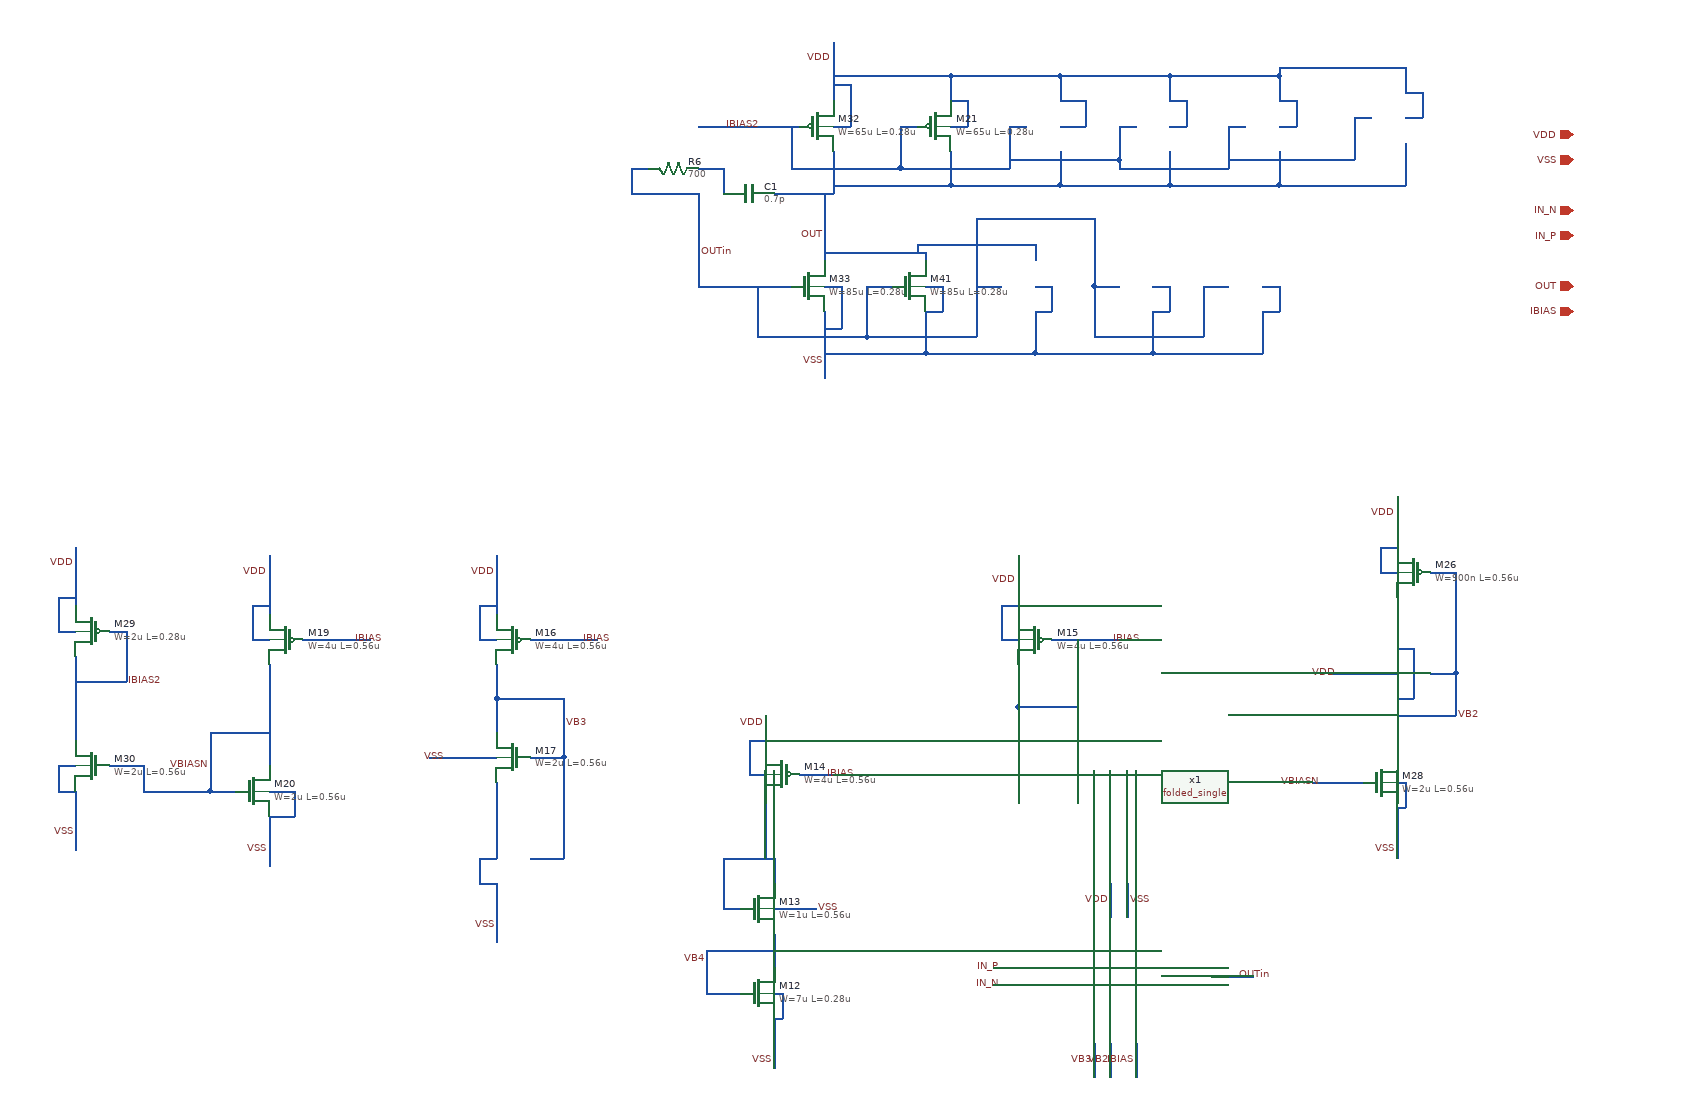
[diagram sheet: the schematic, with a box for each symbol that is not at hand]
v {xschem version=3.1.0 file_version=1.2
}
G {}
K {}
V {}
S {}
E {}
N 120 -50 120 20 {
lab=VDD}
N 100 50 120 50 {
lab=VDD}
N 100 10 100 50 {
lab=VDD}
N 100 10 120 10 {
lab=VDD}
N 160 50 240 50 {
lab=IBIAS}
N 120 80 120 130 {
lab=IBIAS}
N 120 130 190 130 {
lab=IBIAS}
N 190 50 190 130 {
lab=IBIAS}
N 120 130 120 180 {
lab=IBIAS}
N -500 -50 -500 20 {
lab=VDD}
N -520 50 -500 50 {
lab=VDD}
N -520 10 -520 50 {
lab=VDD}
N -520 10 -500 10 {
lab=VDD}
N -460 50 -380 50 {
lab=IBIAS}
N -500 340 -500 410 {
lab=VSS}
N -460 310 -420 310 {
lab=VB3}
N -420 260 -420 310 {
lab=VB3}
N -500 260 -500 280 {
lab=VSS}
N -500 220 -500 260 {
lab=VSS}
N -460 190 -420 190 {
lab=VB3}
N -420 190 -420 260 {
lab=VB3}
N -420 120 -420 190 {
lab=VB3}
N -500 120 -420 120 {
lab=VB3}
N -500 80 -500 120 {
lab=VB3}
N -500 120 -500 160 {
lab=VB3}
N -580 190 -500 190 {
lab=VSS}
N -520 310 -520 340 {
lab=VSS}
N -520 340 -500 340 {
lab=VSS}
N -770 -50 -770 20 {
lab=VDD}
N -790 50 -770 50 {
lab=VDD}
N -790 10 -790 50 {
lab=VDD}
N -790 10 -770 10 {
lab=VDD}
N -730 50 -650 50 {
lab=IBIAS}
N -770 80 -770 200 {
lab=VBIASN}
N -770 260 -770 320 {
lab=VSS}
N -770 230 -740 230 {
lab=VSS}
N -740 230 -740 260 {
lab=VSS}
N -770 260 -740 260 {
lab=VSS}
N -840 230 -810 230 {
lab=VBIASN}
N -840 160 -840 230 {
lab=VBIASN}
N -840 160 -770 160 {
lab=VBIASN}
N 570 120 570 190 {
lab=VB2}
N 570 220 580 220 {
lab=VSS}
N 580 220 580 250 {
lab=VSS}
N 570 250 580 250 {
lab=VSS}
N 570 250 570 310 {
lab=VSS}
N 470 220 530 220 {
lab=VBIASN}
N 550 90 570 90 {
lab=VDD}
N 570 0 570 60 {
lab=VB2}
N 490 90 550 90 {
lab=VDD}
N 570 -120 570 -60 {
lab=VDD}
N 610 -30 640 -30 {
lab=VB2}
N 570 140 640 140 {
lab=VB2}
N 610 90 640 90 {
lab=VB2}
N 550 -30 570 -30 {
lab=VDD}
N 550 -60 550 -30 {
lab=VDD}
N 550 -60 570 -60 {
lab=VDD}
N -1000 -60 -1000 10 {
lab=VDD}
N -1020 40 -1000 40 {
lab=VDD}
N -1020 0 -1020 40 {
lab=VDD}
N -1020 0 -1000 0 {
lab=VDD}
N -1000 230 -1000 300 {
lab=VSS}
N -1020 200 -1000 200 {
lab=VSS}
N -1020 200 -1020 230 {
lab=VSS}
N -1020 230 -1000 230 {
lab=VSS}
N -960 200 -920 200 {
lab=VBIASN}
N -920 200 -920 230 {
lab=VBIASN}
N -920 230 -840 230 {
lab=VBIASN}
N -1000 70 -1000 170 {
lab=IBIAS2}
N -960 40 -940 40 {
lab=IBIAS2}
N -940 40 -940 100 {
lab=IBIAS2}
N -1000 100 -940 100 {
lab=IBIAS2}
N -100 -660 -100 -590 {
lab=VDD}
N -100 -560 -80 -560 {
lab=VDD}
N -80 -610 -80 -560 {
lab=VDD}
N -100 -610 -80 -610 {
lab=VDD}
N -260 -560 -140 -560 {
lab=IBIAS2}
N -170 -480 -100 -480 {
lab=OUT}
N -100 -530 -100 -480 {
lab=OUT}
N -110 -480 -110 -400 {
lab=OUT}
N -110 -340 -110 -260 {
lab=VSS}
N -110 -370 -90 -370 {
lab=VSS}
N -90 -370 -90 -320 {
lab=VSS}
N -110 -320 -90 -320 {
lab=VSS}
N -260 -480 -260 -370 {
lab=OUTin}
N -260 -370 -150 -370 {
lab=OUTin}
N -20 -560 0 -560 {
lab=IBIAS2}
N -20 -560 -20 -510 {
lab=IBIAS2}
N -130 -510 -20 -510 {
lab=IBIAS2}
N -150 -510 -130 -510 {
lab=IBIAS2}
N -150 -560 -150 -510 {
lab=IBIAS2}
N 40 -620 40 -590 {
lab=VDD}
N -100 -620 40 -620 {
lab=VDD}
N 40 -560 60 -560 {
lab=VDD}
N 60 -590 60 -560 {
lab=VDD}
N 40 -590 60 -590 {
lab=VDD}
N 40 -530 40 -490 {
lab=OUT}
N -100 -490 40 -490 {
lab=OUT}
N -340 -510 -320 -510 {
lab=OUTin}
N -340 -510 -340 -480 {
lab=OUTin}
N -340 -480 -260 -480 {
lab=OUTin}
N -230 -510 -230 -480 {
lab=#net1}
N -260 -510 -230 -510 {
lab=#net1}
N 170 -620 170 -590 {
lab=VDD}
N 40 -620 170 -620 {
lab=VDD}
N 170 -530 170 -490 {
lab=OUT}
N 40 -490 170 -490 {
lab=OUT}
N 110 -560 130 -560 {
lab=IBIAS2}
N 110 -560 110 -510 {
lab=IBIAS2}
N -20 -510 110 -510 {
lab=IBIAS2}
N 170 -560 200 -560 {
lab=VDD}
N 200 -590 200 -560 {
lab=VDD}
N 170 -590 200 -590 {
lab=VDD}
N -60 -370 -30 -370 {
lab=OUTin}
N -60 -370 -60 -310 {
lab=OUTin}
N -190 -310 -60 -310 {
lab=OUTin}
N -190 -370 -190 -310 {
lab=OUTin}
N 10 -410 10 -400 {
lab=OUT}
N -110 -410 10 -410 {
lab=OUT}
N 10 -340 10 -290 {
lab=VSS}
N -110 -290 10 -290 {
lab=VSS}
N 10 -370 30 -370 {
lab=VSS}
N 30 -370 30 -340 {
lab=VSS}
N 10 -340 30 -340 {
lab=VSS}
N 300 -620 300 -590 {
lab=VDD}
N 170 -620 300 -620 {
lab=VDD}
N 300 -560 320 -560 {
lab=VDD}
N 320 -590 320 -560 {
lab=VDD}
N 300 -590 320 -590 {
lab=VDD}
N 240 -560 260 -560 {
lab=IBIAS2}
N 240 -560 240 -520 {
lab=IBIAS2}
N 110 -520 240 -520 {
lab=IBIAS2}
N 300 -530 300 -490 {
lab=OUT}
N 170 -490 300 -490 {
lab=OUT}
N 140 -420 140 -400 {
lab=OUT}
N 0 -420 140 -420 {
lab=OUT}
N 0 -420 0 -410 {
lab=OUT}
N 70 -370 100 -370 {
lab=OUTin}
N 70 -370 70 -310 {
lab=OUTin}
N -60 -310 70 -310 {
lab=OUTin}
N 10 -290 140 -290 {
lab=VSS}
N 140 -340 140 -290 {
lab=VSS}
N 140 -370 160 -370 {
lab=VSS}
N 160 -370 160 -340 {
lab=VSS}
N 140 -340 160 -340 {
lab=VSS}
N 430 -620 430 -590 {
lab=VDD}
N 300 -620 430 -620 {
lab=VDD}
N 300 -490 430 -490 {
lab=OUT}
N 430 -530 430 -490 {
lab=OUT}
N 430 -560 450 -560 {
lab=VDD}
N 450 -590 450 -560 {
lab=VDD}
N 430 -590 450 -590 {
lab=VDD}
N 370 -560 390 -560 {
lab=IBIAS2}
N 370 -560 370 -510 {
lab=IBIAS2}
N 240 -510 370 -510 {
lab=IBIAS2}
N 240 -520 240 -510 {
lab=IBIAS2}
N 210 -370 240 -370 {
lab=OUTin}
N 210 -370 210 -310 {
lab=OUTin}
N 280 -340 280 -290 {
lab=VSS}
N 280 -370 300 -370 {
lab=VSS}
N 300 -370 300 -340 {
lab=VSS}
N 280 -340 300 -340 {
lab=VSS}
N 340 -370 370 -370 {
lab=OUTin}
N 340 -370 340 -310 {
lab=OUTin}
N 210 -310 340 -310 {
lab=OUTin}
N 280 -290 410 -290 {
lab=VSS}
N 410 -340 410 -290 {
lab=VSS}
N 410 -370 430 -370 {
lab=VSS}
N 430 -370 430 -340 {
lab=VSS}
N 410 -340 430 -340 {
lab=VSS}
N 140 -290 280 -290 {
lab=VSS}
N 210 -450 210 -370 {
lab=OUTin}
N 70 -450 210 -450 {
lab=OUTin}
N 70 -450 70 -360 {
lab=OUTin}
N 580 -630 580 -600 {
lab=VDD}
N 580 -540 580 -500 {
lab=OUT}
N 580 -570 600 -570 {
lab=VDD}
N 600 -600 600 -570 {
lab=VDD}
N 580 -600 600 -600 {
lab=VDD}
N 520 -570 540 -570 {
lab=IBIAS2}
N 520 -570 520 -520 {
lab=IBIAS2}
N 430 -630 580 -630 {
lab=VDD}
N 430 -630 430 -620 {
lab=VDD}
N 580 -500 580 -490 {
lab=OUT}
N 430 -490 580 -490 {
lab=OUT}
N 370 -520 520 -520 {
lab=IBIAS2}
N -170 470 -160 470 {
lab=VSS}
N -160 470 -160 500 {
lab=VSS}
N -170 500 -160 500 {
lab=VSS}
N -170 500 -170 560 {
lab=VSS}
N -170 370 -120 370 {
lab=VSS}
N -170 400 -170 440 {
lab=VB4}
N -230 370 -210 370 {
lab=#net2}
N -230 310 -230 370 {
lab=#net2}
N -230 310 -170 310 {
lab=#net2}
N -170 310 -170 340 {
lab=#net2}
N -180 240 -180 310 {
lab=#net2}
N -180 140 -180 180 {
lab=VDD}
N -200 210 -180 210 {
lab=VDD}
N -200 170 -200 210 {
lab=VDD}
N -200 170 -180 170 {
lab=VDD}
N -140 210 -100 210 {
lab=IBIAS}
N -250 420 -170 420 {
lab=VB4}
N -250 420 -250 470 {
lab=VB4}
N -250 470 -210 470 {
lab=VB4}
N 640 -30 640 30 {
lab=VB2}
N 640 90 640 140 {
lab=VB2}
N 640 30 640 90 {
lab=VB2}
N 570 120 590 120 {
lab=VB2}
N 590 60 590 120 {
lab=VB2}
N 570 60 590 60 {
lab=VB2}
N -520 310 -500 310 {
lab=VSS}
N -500 280 -500 310 {
lab=VSS}
N 230 340 230 380 {
lab=VDD}
N 250 340 250 380 {
lab=VSS}
N 350 450 400 450 {
lab=OUTin}
N 90 440 140 440 {
lab=IN_P}
N 90 460 140 460 {
lab=IN_N}
N 210 530 210 570 {
lab=VB3}
N 230 530 230 570 {
lab=VB2}
N 260 530 260 570 {
lab=IBIAS}
C {symbols/pfet_03v3.sym} 140 50 0 1 {name=M15
L=0.56u
W=4u
nf=1
m=1
ad="'int((nf+1)/2) * W/nf * 0.18u'"
pd="'2*int((nf+1)/2) * (W/nf + 0.18u)'"
as="'int((nf+2)/2) * W/nf * 0.18u'"
ps="'2*int((nf+2)/2) * (W/nf + 0.18u)'"
nrd="'0.18u / W'" nrs="'0.18u / W'"
sa=0 sb=0 sd=0
model=pfet_03v3
spiceprefix=X
}
C {devices/lab_wire.sym} 120 -20 0 0 {name=p10 sig_type=std_logic lab=VDD}
C {devices/lab_wire.sym} 230 50 0 1 {name=p14 sig_type=std_logic lab=IBIAS}
C {symbols/pfet_03v3.sym} -480 50 0 1 {name=M16
L=0.56u
W=4u
nf=1
m=1
ad="'int((nf+1)/2) * W/nf * 0.18u'"
pd="'2*int((nf+1)/2) * (W/nf + 0.18u)'"
as="'int((nf+2)/2) * W/nf * 0.18u'"
ps="'2*int((nf+2)/2) * (W/nf + 0.18u)'"
nrd="'0.18u / W'" nrs="'0.18u / W'"
sa=0 sb=0 sd=0
model=pfet_03v3
spiceprefix=X
}
C {devices/lab_wire.sym} -500 -30 0 0 {name=p24 sig_type=std_logic lab=VDD}
C {devices/lab_wire.sym} -400 50 0 1 {name=p25 sig_type=std_logic lab=IBIAS}
C {symbols/nfet_03v3.sym} -480 190 0 1 {name=M17
L=0.56u
W=2u
nf=1
m=1
ad="'int((nf+1)/2) * W/nf * 0.18u'"
pd="'2*int((nf+1)/2) * (W/nf + 0.18u)'"
as="'int((nf+2)/2) * W/nf * 0.18u'"
ps="'2*int((nf+2)/2) * (W/nf + 0.18u)'"
nrd="'0.18u / W'" nrs="'0.18u / W'"
sa=0 sb=0 sd=0
model=nfet_03v3
spiceprefix=X
}
C {devices/lab_wire.sym} -560 190 0 0 {name=p26 sig_type=std_logic lab=VSS}
C {devices/lab_wire.sym} -420 150 0 1 {name=p27 sig_type=std_logic lab=VB3}
C {symbols/pfet_03v3.sym} -750 50 0 1 {name=M19
L=0.56u
W=4u
nf=1
m=1
ad="'int((nf+1)/2) * W/nf * 0.18u'"
pd="'2*int((nf+1)/2) * (W/nf + 0.18u)'"
as="'int((nf+2)/2) * W/nf * 0.18u'"
ps="'2*int((nf+2)/2) * (W/nf + 0.18u)'"
nrd="'0.18u / W'" nrs="'0.18u / W'"
sa=0 sb=0 sd=0
model=pfet_03v3
spiceprefix=X
}
C {devices/lab_wire.sym} -770 -30 0 0 {name=p28 sig_type=std_logic lab=VDD}
C {devices/lab_wire.sym} -670 50 0 1 {name=p29 sig_type=std_logic lab=IBIAS}
C {symbols/nfet_03v3.sym} -790 230 0 0 {name=M20
L=0.56u
W=2u
nf=1
m=1
ad="'int((nf+1)/2) * W/nf * 0.18u'"
pd="'2*int((nf+1)/2) * (W/nf + 0.18u)'"
as="'int((nf+2)/2) * W/nf * 0.18u'"
ps="'2*int((nf+2)/2) * (W/nf + 0.18u)'"
nrd="'0.18u / W'" nrs="'0.18u / W'"
sa=0 sb=0 sd=0
model=nfet_03v3
spiceprefix=X
}
C {devices/lab_wire.sym} -840 200 0 0 {name=p30 sig_type=std_logic lab=VBIASN}
C {symbols/pfet_03v3.sym} 590 -30 0 1 {name=M26
L=0.56u
W=900n
nf=1
m=1
ad="'int((nf+1)/2) * W/nf * 0.18u'"
pd="'2*int((nf+1)/2) * (W/nf + 0.18u)'"
as="'int((nf+2)/2) * W/nf * 0.18u'"
ps="'2*int((nf+2)/2) * (W/nf + 0.18u)'"
nrd="'0.18u / W'" nrs="'0.18u / W'"
sa=0 sb=0 sd=0
model=pfet_03v3
spiceprefix=X
}
C {symbols/nfet_03v3.sym} 550 220 0 0 {name=M28
L=0.56u
W=2u
nf=1
m=1
ad="'int((nf+1)/2) * W/nf * 0.18u'"
pd="'2*int((nf+1)/2) * (W/nf + 0.18u)'"
as="'int((nf+2)/2) * W/nf * 0.18u'"
ps="'2*int((nf+2)/2) * (W/nf + 0.18u)'"
nrd="'0.18u / W'" nrs="'0.18u / W'"
sa=0 sb=0 sd=0
model=nfet_03v3
spiceprefix=X
}
C {devices/lab_wire.sym} 570 -100 0 0 {name=p39 sig_type=std_logic lab=VDD}
C {devices/lab_wire.sym} 500 90 0 0 {name=p40 sig_type=std_logic lab=VDD}
C {devices/lab_wire.sym} 570 300 0 0 {name=p41 sig_type=std_logic lab=VSS}
C {devices/lab_wire.sym} 480 220 0 0 {name=p42 sig_type=std_logic lab=VBIASN}
C {devices/lab_wire.sym} 640 140 0 1 {name=p43 sig_type=std_logic lab=VB2}
C {devices/lab_wire.sym} -500 390 0 0 {name=p48 sig_type=std_logic lab=VSS}
C {devices/lab_wire.sym} -770 300 0 0 {name=p52 sig_type=std_logic lab=VSS}
C {symbols/pfet_03v3.sym} -980 40 0 1 {name=M29
L=0.28u
W=2u
nf=1
m=1
ad="'int((nf+1)/2) * W/nf * 0.18u'"
pd="'2*int((nf+1)/2) * (W/nf + 0.18u)'"
as="'int((nf+2)/2) * W/nf * 0.18u'"
ps="'2*int((nf+2)/2) * (W/nf + 0.18u)'"
nrd="'0.18u / W'" nrs="'0.18u / W'"
sa=0 sb=0 sd=0
model=pfet_03v3
spiceprefix=X
}
C {devices/lab_wire.sym} -1000 -40 0 0 {name=p53 sig_type=std_logic lab=VDD}
C {symbols/nfet_03v3.sym} -980 200 0 1 {name=M30
L=0.56u
W=2u
nf=1
m=1
ad="'int((nf+1)/2) * W/nf * 0.18u'"
pd="'2*int((nf+1)/2) * (W/nf + 0.18u)'"
as="'int((nf+2)/2) * W/nf * 0.18u'"
ps="'2*int((nf+2)/2) * (W/nf + 0.18u)'"
nrd="'0.18u / W'" nrs="'0.18u / W'"
sa=0 sb=0 sd=0
model=nfet_03v3
spiceprefix=X
}
C {devices/lab_wire.sym} -940 100 0 1 {name=p54 sig_type=std_logic lab=IBIAS2}
C {symbols/pfet_03v3.sym} -120 -560 0 0 {name=M32
L=0.28u
W=65u
nf=1
m=1
ad="'int((nf+1)/2) * W/nf * 0.18u'"
pd="'2*int((nf+1)/2) * (W/nf + 0.18u)'"
as="'int((nf+2)/2) * W/nf * 0.18u'"
ps="'2*int((nf+2)/2) * (W/nf + 0.18u)'"
nrd="'0.18u / W'" nrs="'0.18u / W'"
sa=0 sb=0 sd=0
model=pfet_03v3
spiceprefix=X
}
C {symbols/nfet_03v3.sym} -130 -370 0 0 {name=M33
L=0.28u
W=85u
nf=1
m=1
ad="'int((nf+1)/2) * W/nf * 0.18u'"
pd="'2*int((nf+1)/2) * (W/nf + 0.18u)'"
as="'int((nf+2)/2) * W/nf * 0.18u'"
ps="'2*int((nf+2)/2) * (W/nf + 0.18u)'"
nrd="'0.18u / W'" nrs="'0.18u / W'"
sa=0 sb=0 sd=0
model=nfet_03v3
spiceprefix=X
}
C {devices/lab_wire.sym} -100 -640 0 0 {name=p55 sig_type=std_logic lab=VDD}
C {devices/lab_wire.sym} -110 -280 0 0 {name=p56 sig_type=std_logic lab=VSS}
C {devices/res.sym} -290 -510 1 0 {name=R6
value=700
footprint=1206
device=resistor
m=1}
C {symbols/nfet_03v3.sym} -10 -370 0 0 {name=M41
L=0.28u
W=85u
nf=1
m=1
ad="'int((nf+1)/2) * W/nf * 0.18u'"
pd="'2*int((nf+1)/2) * (W/nf + 0.18u)'"
as="'int((nf+2)/2) * W/nf * 0.18u'"
ps="'2*int((nf+2)/2) * (W/nf + 0.18u)'"
nrd="'0.18u / W'" nrs="'0.18u / W'"
sa=0 sb=0 sd=0
model=nfet_03v3
spiceprefix=X
}
C {devices/lab_wire.sym} -110 -430 0 0 {name=p62 sig_type=std_logic lab=OUT
}
C {devices/lab_wire.sym} -230 -560 0 1 {name=p64 sig_type=std_logic lab=IBIAS2}
C {devices/lab_wire.sym} -260 -410 0 1 {name=p60 sig_type=std_logic lab=OUTin}
C {devices/lab_wire.sym} -1000 280 0 0 {name=p67 sig_type=std_logic lab=VSS}
C {devices/iopin.sym} 780 -550 0 0 {name=p65 lab=VDD}
C {devices/iopin.sym} 780 -520 0 0 {name=p66 lab=VSS}
C {devices/iopin.sym} 780 -460 0 0 {name=p69 lab=IN_N}
C {devices/iopin.sym} 780 -430 0 0 {name=p70 lab=IN_P}
C {devices/iopin.sym} 780 -370 0 0 {name=p72 lab=OUT}
C {devices/iopin.sym} 780 -340 0 0 {name=p73 lab=IBIAS}
C {symbols/nfet_03v3.sym} -190 470 0 0 {name=M12
L=0.28u
W=7u
nf=1
m=1
ad="'int((nf+1)/2) * W/nf * 0.18u'"
pd="'2*int((nf+1)/2) * (W/nf + 0.18u)'"
as="'int((nf+2)/2) * W/nf * 0.18u'"
ps="'2*int((nf+2)/2) * (W/nf + 0.18u)'"
nrd="'0.18u / W'" nrs="'0.18u / W'"
sa=0 sb=0 sd=0
model=nfet_03v3
spiceprefix=X
}
C {devices/lab_wire.sym} -170 550 0 0 {name=p9 sig_type=std_logic lab=VSS}
C {symbols/nfet_03v3.sym} -190 370 0 0 {name=M13
L=0.56u
W=1u
nf=1
m=1
ad="'int((nf+1)/2) * W/nf * 0.18u'"
pd="'2*int((nf+1)/2) * (W/nf + 0.18u)'"
as="'int((nf+2)/2) * W/nf * 0.18u'"
ps="'2*int((nf+2)/2) * (W/nf + 0.18u)'"
nrd="'0.18u / W'" nrs="'0.18u / W'"
sa=0 sb=0 sd=0
model=nfet_03v3
spiceprefix=X
}
C {symbols/pfet_03v3.sym} -160 210 0 1 {name=M14
L=0.56u
W=4u
nf=1
m=1
ad="'int((nf+1)/2) * W/nf * 0.18u'"
pd="'2*int((nf+1)/2) * (W/nf + 0.18u)'"
as="'int((nf+2)/2) * W/nf * 0.18u'"
ps="'2*int((nf+2)/2) * (W/nf + 0.18u)'"
nrd="'0.18u / W'" nrs="'0.18u / W'"
sa=0 sb=0 sd=0
model=pfet_03v3
spiceprefix=X
}
C {devices/lab_wire.sym} -180 150 0 0 {name=p13 sig_type=std_logic lab=VDD}
C {devices/lab_wire.sym} -120 370 0 1 {name=p15 sig_type=std_logic lab=VSS}
C {devices/lab_wire.sym} -110 210 0 1 {name=p12 sig_type=std_logic lab=IBIAS}
C {devices/lab_wire.sym} -250 430 0 0 {name=p11 sig_type=std_logic lab=VB4}
C {symbols/pfet_03v3.sym} 20 -560 0 0 {name=M21
L=0.28u
W=65u
nf=1
m=1
ad="'int((nf+1)/2) * W/nf * 0.18u'"
pd="'2*int((nf+1)/2) * (W/nf + 0.18u)'"
as="'int((nf+2)/2) * W/nf * 0.18u'"
ps="'2*int((nf+2)/2) * (W/nf + 0.18u)'"
nrd="'0.18u / W'" nrs="'0.18u / W'"
sa=0 sb=0 sd=0
model=pfet_03v3
spiceprefix=X
}
C {devices/capa.sym} -200 -480 3 0 {name=C1
m=1
value=0.7p
footprint=1206
device="ceramic capacitor"}
C {devices/lab_wire.sym} 230 360 0 0 {name=p31 sig_type=std_logic lab=VDD}
C {devices/lab_wire.sym} 250 360 0 1 {name=p32 sig_type=std_logic lab=VSS}
C {devices/lab_wire.sym} 210 550 3 0 {name=p33 sig_type=std_logic lab=VB3}
C {devices/lab_wire.sym} 230 550 3 0 {name=p34 sig_type=std_logic lab=VB2}
C {devices/lab_wire.sym} 260 550 1 1 {name=p36 sig_type=std_logic lab=IBIAS}
C {devices/lab_wire.sym} 380 450 0 1 {name=p37 sig_type=std_logic lab=OUTin}
C {devices/lab_wire.sym} 100 460 0 0 {name=p38 sig_type=std_logic lab=IN_N}
C {devices/lab_wire.sym} 100 440 0 0 {name=p44 sig_type=std_logic lab=IN_P}
C {folded_single.sym} 240 450 0 0 {name=x1}
